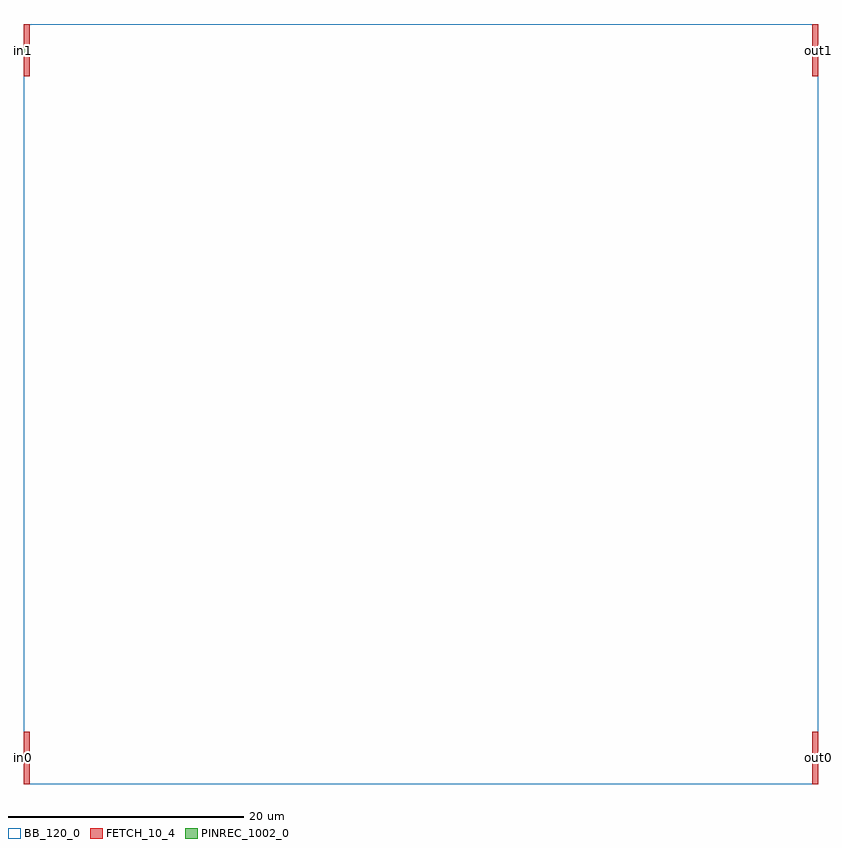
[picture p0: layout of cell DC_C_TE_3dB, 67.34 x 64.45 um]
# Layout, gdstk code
import gdstk
lib = gdstk.Library(unit=1e-6, precision=1e-09)
def R(c, l, rs):  # rectangles x0, y0, x1, y1
    for r in rs: c.add(gdstk.rectangle(r[:2], r[2:], *l))
FETCH_10_4 = (10, 4)
BB_120_0 = (120, 0)
PINREC_1002_0 = (1002, 0)

dc_c_te_3db = lib.new_cell('DC_C_TE_3dB')
R(dc_c_te_3db, FETCH_10_4, [(0,0,0.5,2), (66.837,0,67.337,2), (0,2.45,0.5,4.45), (66.837,2.45,67.337,4.45), (0,60,0.5,62), (66.837,60,67.337,62), (0,62.45,0.5,64.45), (66.837,62.45,67.337,64.45)])
R(dc_c_te_3db, BB_120_0, [(0,0,67.337,64.45)])
R(dc_c_te_3db, PINREC_1002_0, [(0,2,0.5,2.45), (66.837,2,67.337,2.45), (0,62,0.5,62.45), (66.837,62,67.337,62.45)])
dc_c_te_3db.add(gdstk.Label('out0', (67.337,2.219), layer=1000, texttype=0))
dc_c_te_3db.add(gdstk.Label('out1', (67.337,62.23), layer=1000, texttype=0))
dc_c_te_3db.add(gdstk.Label('in1', (0,62.215), layer=1000, texttype=0))
dc_c_te_3db.add(gdstk.Label('in0', (0,2.237), layer=1000, texttype=0))

lib.write_gds('DC_C_TE_3dB.gds')
